# CHARACTERIZATION PROVENANCE
# CHAR_STATUS: ESTIMATED_SCALAR
# WARNING: This Liberty file is generated from analytical models,
# NOT from silicon measurement or SPICE post-layout simulation.
# Timing values are estimated from Landau-Khalatnikov transient simulation.
# NOT suitable for signoff or tapeout. Educational/research use only.
# For production characterization, use Cadence Liberate or Synopsys SiliconSmart
# with measured device data.
VERSION 5.8 ;
BUSBITCHARS "[]" ;
DIVIDERCHAR "/" ;

# Minimal layer definition for standalone validation
LAYER met1
  TYPE ROUTING ;
  DIRECTION HORIZONTAL ;
  PITCH 0.46 ;
  WIDTH 0.14 ;
END met1

# Site definition for placement
SITE fecim_site
  CLASS CORE ;
  SIZE 0.460 BY 2.720 ;
  SYMMETRY X Y ;
END fecim_site

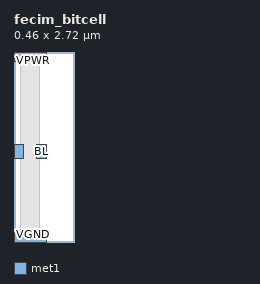
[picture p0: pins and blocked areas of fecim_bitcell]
MACRO fecim_bitcell
  CLASS CORE ;
  ORIGIN 0 0 ;
  SIZE 0.460 BY 2.720 ;
  SYMMETRY X Y ;
  SITE fecim_site ;

  PIN WL
    DIRECTION INPUT ;
    USE SIGNAL ;
    PORT
      LAYER met1 ;
      RECT 0.000 1.200 0.140 1.400 ;
    END
  END WL

  PIN BL
    DIRECTION OUTPUT ;
    USE SIGNAL ;
    PORT
      LAYER met1 ;
      RECT 0.320 1.200 0.460 1.400 ;
    END
  END BL

  PIN VPWR
    DIRECTION INOUT ;
    USE POWER ;
    PORT
      LAYER met1 ;
      RECT 0.000 2.580 0.460 2.720 ;
    END
  END VPWR

  PIN VGND
    DIRECTION INOUT ;
    USE GROUND ;
    PORT
      LAYER met1 ;
      RECT 0.000 0.000 0.460 0.140 ;
    END
  END VGND

  OBS
    LAYER met1 ;
    RECT 0.100 0.100 0.360 2.620 ;
  END

END fecim_bitcell

END LIBRARY
